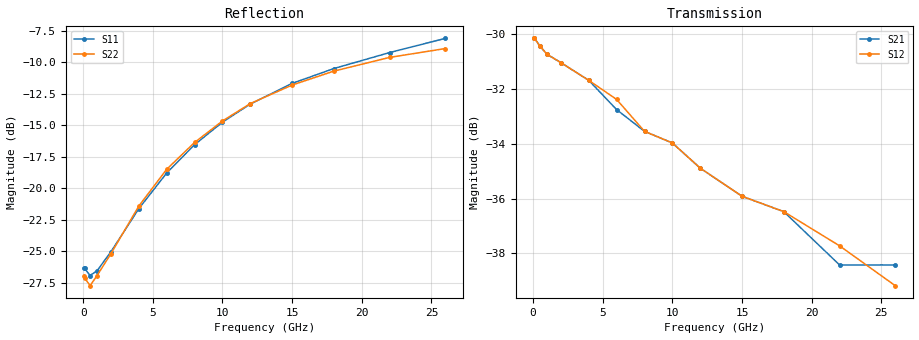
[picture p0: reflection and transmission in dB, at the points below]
! HMMC-1001
! Typical S-parameters at Maximum Attenuation Setting, TA = 25 C
# ghz s ma r 50
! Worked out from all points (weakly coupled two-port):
!   14 points, 45 MHz to 26 GHz, reference 50 ohm
!   highest |S21| = -30.17 dB at 45 MHz (marker M1); lowest = -38.4 dB at 22 GHz (marker M2)
!   lowest |S11| = -26.9 dB at 500 MHz (marker M3), VSWR 1.09, Z = 54.5 - j1.32 ohm
!   |S11| at or under -10 dB: start of sweep to 19.53 GHz
!   |S22| runs from -27.7 to -8.9 dB; largest |S21 - S12| = 0.0014
!   S11 on the Smith chart (normalised r, x): 45 MHz: 1.10, -0.00; 8 GHz: 0.82, -0.21; 15 GHz: 0.59, -0.02; 26 GHz: 0.57, +0.48
0.045  0.048 -2.0  0.031 -0.6  0.031 -0.9  0.045 -2.7
0.1  0.048 -5.0  0.031 -1.7  0.031 -2.2  0.044 -6.3
0.5  0.045 -15.6  0.03 -5.7  0.03 -5.4  0.041 -17.1
1  0.047 -27.9  0.029 -10.4  0.029 -10.2  0.045 -31.0
2  0.056 -50.0  0.028 -19.3  0.028 -19.4  0.055 -53.8
4  0.083 -82.0  0.026 -35.4  0.026 -35.6  0.085 -84.4
6  0.115 -104.8  0.023 -49.2  0.024 -49.2  0.119 -105.3
8  0.149 -123.3  0.021 -61.4  0.021 -62.0  0.152 -123.1
10  0.183 -139.9  0.02 -73.3  0.02 -73.4  0.185 -138.9
12  0.216 -155.4  0.018 -84.0  0.018 -82.6  0.217 -153.8
15  0.261 -176.7  0.016 -97.3  0.016 -99.3  0.257 -174.9
18  0.299 163.7  0.015 -110.8  0.015 -112.3  0.292 165.2
22  0.346 140.0  0.012 -130.3  0.013 -134.5  0.331 140.4
26  0.394 114.5  0.012 -150.4  0.011 -147.2  0.359 114.7
